One B-rep face of a CAD part: STEP entity #1581.
In plain terms, the planar face has unit normal (1, 0, 0).
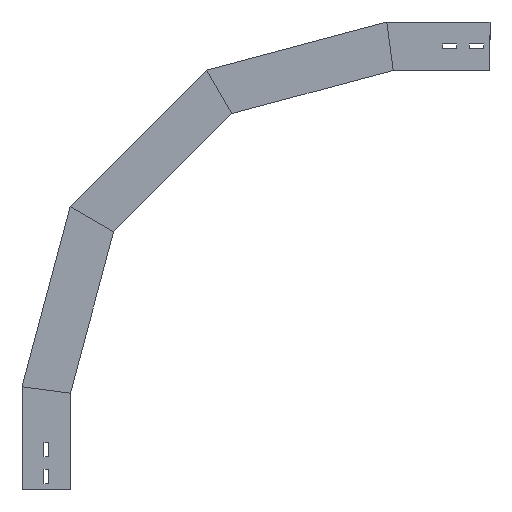
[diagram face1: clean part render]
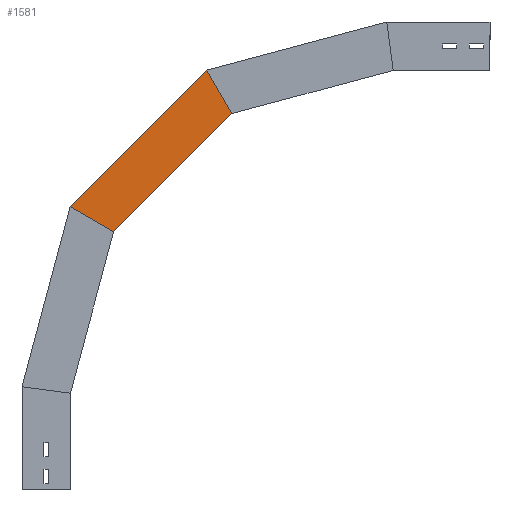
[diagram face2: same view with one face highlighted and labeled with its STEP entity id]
Its self-contained STEP definition (entity closure, numbers rounded to 3 decimals):
#73 = VERTEX_POINT ( 'NONE', #1717 ) ;
#116 = ORIENTED_EDGE ( 'NONE', *, *, #712, .F. ) ;
#138 = VERTEX_POINT ( 'NONE', #160 ) ;
#157 = DIRECTION ( 'NONE',  ( 0., -0.5, -0.866 ) ) ;
#160 = CARTESIAN_POINT ( 'NONE',  ( 0., -67.034, 400.175 ) ) ;
#180 = DIRECTION ( 'NONE',  ( 0., -0.866, -0.5 ) ) ;
#187 = ORIENTED_EDGE ( 'NONE', *, *, #1735, .F. ) ;
#323 = VERTEX_POINT ( 'NONE', #1074 ) ;
#333 = ORIENTED_EDGE ( 'NONE', *, *, #1455, .T. ) ;
#464 = LINE ( 'NONE', #1770, #1395 ) ;
#490 = LINE ( 'NONE', #1776, #1380 ) ;
#501 = PLANE ( 'NONE',  #719 ) ;
#544 = VERTEX_POINT ( 'NONE', #735 ) ;
#626 = VECTOR ( 'NONE', #157, 1000. ) ;
#688 = VECTOR ( 'NONE', #855, 1000. ) ;
#712 = EDGE_CURVE ( 'NONE', #323, #138, #490, .T. ) ;
#719 = AXIS2_PLACEMENT_3D ( 'NONE', #1387, #962, #1539 ) ;
#735 = CARTESIAN_POINT ( 'NONE',  ( 0., -250.175, 583.315 ) ) ;
#793 = FACE_OUTER_BOUND ( 'NONE', #931, .T. ) ;
#855 = DIRECTION ( 'NONE',  ( 0., -0.707, 0.707 ) ) ;
#931 = EDGE_LOOP ( 'NONE', ( #333, #1337, #187, #116 ) ) ;
#962 = DIRECTION ( 'NONE',  ( 1., 0., 0. ) ) ;
#1035 = DIRECTION ( 'NONE',  ( 0., -0.707, 0.707 ) ) ;
#1055 = CARTESIAN_POINT ( 'NONE',  ( 0., -286.565, 520.285 ) ) ;
#1074 = CARTESIAN_POINT ( 'NONE',  ( 0., 0.209, 438.998 ) ) ;
#1337 = ORIENTED_EDGE ( 'NONE', *, *, #1492, .T. ) ;
#1380 = VECTOR ( 'NONE', #180, 1000. ) ;
#1387 = CARTESIAN_POINT ( 'NONE',  ( 0., -51.332, 384.473 ) ) ;
#1395 = VECTOR ( 'NONE', #1035, 1000. ) ;
#1429 = LINE ( 'NONE', #1442, #688 ) ;
#1442 = CARTESIAN_POINT ( 'NONE',  ( 0., -51.332, 384.473 ) ) ;
#1455 = EDGE_CURVE ( 'NONE', #323, #73, #464, .T. ) ;
#1486 = LINE ( 'NONE', #1055, #626 ) ;
#1492 = EDGE_CURVE ( 'NONE', #73, #544, #1486, .T. ) ;
#1539 = DIRECTION ( 'NONE',  ( 0., 0., -1. ) ) ;
#1581 = ADVANCED_FACE ( 'NONE', ( #793 ), #501, .T. ) ;
#1717 = CARTESIAN_POINT ( 'NONE',  ( 0., -211.352, 650.559 ) ) ;
#1735 = EDGE_CURVE ( 'NONE', #138, #544, #1429, .T. ) ;
#1770 = CARTESIAN_POINT ( 'NONE',  ( 0., 1.701, 437.506 ) ) ;
#1776 = CARTESIAN_POINT ( 'NONE',  ( 0., -127.544, 365.239 ) ) ;
